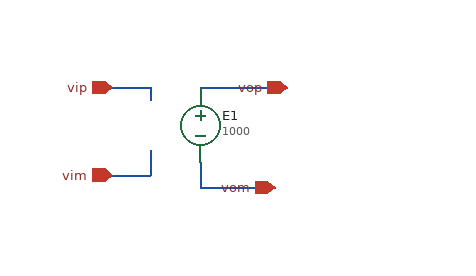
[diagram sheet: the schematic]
v {xschem version=3.4.8RC file_version=1.2}
G {}
K {}
V {}
S {}
E {}
N 120 -60 190 -60 {lab=vop}
N 120 20 180 20 {lab=vom}
N 120 0 120 20 {lab=vom}
N 50 10 80 10 {lab=vim}
N 80 -10 80 10 {lab=vim}
N 50 -60 70 -60 {lab=vip}
N 70 -60 80 -60 {lab=vip}
N 80 -60 80 -50 {lab=vip}
C {vcvs.sym} 120 -30 0 0 {name=E1 value=1000}
C {iopin.sym} 190 -60 0 0 {name=p1 lab=vop}
C {iopin.sym} 180 20 0 0 {name=p2 lab=vom}
C {iopin.sym} 50 10 2 0 {name=p3 lab=vim}
C {iopin.sym} 50 -60 2 0 {name=p4 lab=vip
}
